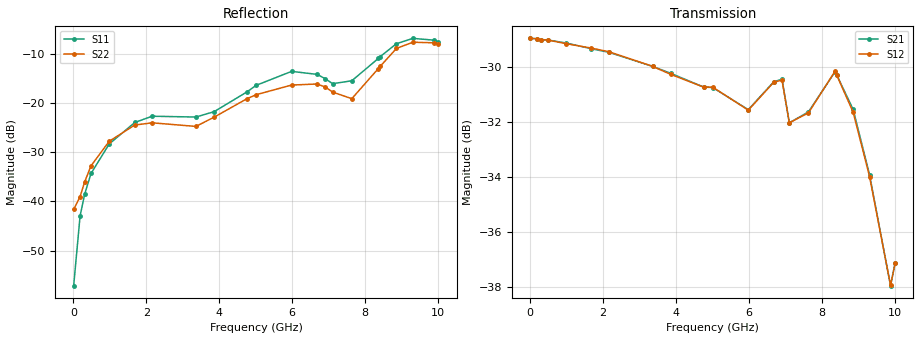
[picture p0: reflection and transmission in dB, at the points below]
! Device ID: PE43705
! Serial: 1
! Insertion: A
! Impedance: 50 ohm
! Temp: 25C
! VDD: 3.400V
! Attenuation Step: 28.00dB
#  Hz  S  RI  R  50
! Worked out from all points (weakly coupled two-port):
!   401 points, 10 MHz to 10.01 GHz, reference 50 ohm
!   highest |S21| = -28.97 dB at 10 MHz (marker M1); lowest = -37.9 dB at 9.885 GHz (marker M2)
!   lowest |S11| = -57.1 dB at 10 MHz (marker M3), VSWR 1.00, Z = 49.9 + j0.044 ohm
!   |S11| at or under -10 dB: start of sweep to 8.494 GHz
!   |S22| runs from -41.7 to -7.5 dB; largest |S21 - S12| = 0.00069
!   S11 on the Smith chart (normalised r, x): 10 MHz: 1.00, +0.00; 4.76 GHz: 0.80, +0.12; 8.41 GHz: 0.80, +0.52; 9.31 GHz: 0.52, +0.55; 10.01 GHz: 0.47, +0.33
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1e7  -0.00132 0.000441  0.0356 -8.6e-05  0.0356 -9.7e-05  -0.00828 0.000512
1.85e8  -0.00176 0.00687  0.0355 -0.00166  0.0355 -0.00168  -0.00804 0.00774
3.1e8  -0.00367 0.0112  0.0353 -0.00278  0.0353 -0.00277  -0.00966 0.0124
4.85e8  -0.00834 0.0173  0.0351 -0.00431  0.0351 -0.00428  -0.0135 0.0186
9.85e8  -0.0308 0.0229  0.0339 -0.00839  0.0338 -0.00839  -0.032 0.0254
1.685e9  -0.0625 0.0103  0.0313 -0.0135  0.0314 -0.0135  -0.057 0.0177
2.16e9  -0.0732 -0.00424  0.0292 -0.0166  0.0293 -0.0166  -0.0624 0.00767
3.36e9  -0.0719 -0.00317  0.0223 -0.0225  0.0224 -0.0224  -0.0565 0.0121
3.86e9  -0.0786 0.0217  0.0195 -0.0238  0.0194 -0.0237  -0.0665 0.0268
4.76e9  -0.1056 0.0749  0.0148 -0.025  0.0148 -0.025  -0.0938 0.0583
5.01e9  -0.1212 0.0899  0.0138 -0.0255  0.0139 -0.0255  -0.1028 0.0643
5.985e9  -0.1754 0.1144  0.0083 -0.0251  0.00844 -0.025  -0.1297 0.0794
6.685e9  -0.1666 0.1016  0.00647 -0.029  0.00661 -0.0289  -0.1376 0.0732
6.91e9  -0.1474 0.0964  0.00262 -0.0299  0.00255 -0.0298  -0.1257 0.0727
7.11e9  -0.1315 0.086  0.00102 -0.025  0.00123 -0.025  -0.1047 0.0754
7.635e9  -0.0823 0.1465  0.00225 -0.0261  0.00215 -0.026  -0.0558 0.0954
8.36e9  -0.0224 0.2822  -0.00675 -0.0302  -0.00705 -0.0302  -0.0364 0.2202
8.41e9  -0.0255 0.2937  -0.00799 -0.0295  -0.0079 -0.0295  -0.0394 0.2314
8.86e9  -0.0752 0.3932  -0.0136 -0.0227  -0.013 -0.0227  -0.0971 0.3448
9.31e9  -0.1619 0.4234  -0.0125 -0.0158  -0.012 -0.016  -0.1891 0.3683
9.885e9  -0.284 0.3291  -0.0038 -0.0121  -0.00387 -0.0121  -0.325 0.2477
1.001e10  -0.2993 0.2897  -0.00194 -0.0138  -0.00184 -0.0138  -0.3469 0.1984
